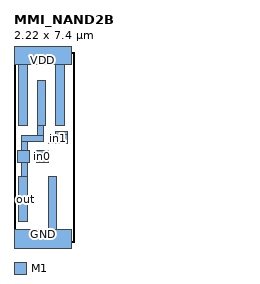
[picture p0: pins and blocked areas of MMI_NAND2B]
MACRO MMI_NAND2B
	CLASS CORE ;
	FOREIGN MMI_NAND2B 0 0 ;
	SIZE 2.22 BY 7.4 ;
	SYMMETRY X Y ;
	SITE CORE1 ;
	PIN out
		DIRECTION output ;
		USE SIGNAL ;
		PORT
			LAYER M1 ;
			RECT 0.9 4.54 1.24 6.3 ;
			LAYER M1 ;
			RECT 0.9 4.135 1.13 4.54 ;
			LAYER M1 ;
			RECT 0.29 3.905 1.13 4.135 ;
			LAYER M1 ;
			RECT 0.29 3.555 0.52 3.905 ;
			LAYER M1 ;
			RECT 0.145 3.105 0.595 3.555 ;
			LAYER M1 ;
			RECT 0.29 2.54 0.52 3.105 ;
			LAYER M1 ;
			RECT 0.18 0.78 0.52 2.54 ;
		END
		AntennaDiffArea 1.8768 ;
	END out
	PIN in1
		DIRECTION input ;
		USE SIGNAL ;
		PORT
			LAYER M1 ;
			RECT 1.625 4.19 2.075 4.295 ;
			LAYER M1 ;
			RECT 1.36 3.85 2.075 4.19 ;
			LAYER M1 ;
			RECT 1.625 3.845 2.075 3.85 ;
		END
		AntennaGateArea 0.6624 ;
	END in1
	PIN GND
		DIRECTION inout ;
		USE GROUND ;
		PORT
			LAYER M1 ;
			RECT 1.33 0.5 1.67 2.54 ;
			LAYER M1 ;
			RECT 0 -0.5 2.22 0.5 ;
		END
	END GND
	PIN VDD
		DIRECTION inout ;
		USE POWER ;
		PORT
			LAYER M1 ;
			RECT 0 6.9 2.22 7.9 ;
			LAYER M1 ;
			RECT 0.18 4.54 0.52 6.9 ;
			LAYER M1 ;
			RECT 1.62 4.54 1.96 6.9 ;
		END
	END VDD
	PIN in0
		DIRECTION input ;
		USE SIGNAL ;
		PORT
			LAYER M1 ;
			RECT 0.885 3.5 1.335 3.555 ;
			LAYER M1 ;
			RECT 0.825 3.16 1.335 3.5 ;
			LAYER M1 ;
			RECT 0.885 3.105 1.335 3.16 ;
		END
		AntennaGateArea 0.6624 ;
	END in0
	OBS
	END
END MMI_NAND2B
